VERSION 5.8 ;
BUSBITCHARS "[]" ;
DIVIDERCHAR "/" ;
UNITS
    DATABASE MICRONS 1000 ;
END UNITS

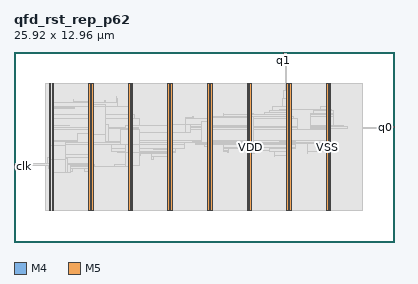
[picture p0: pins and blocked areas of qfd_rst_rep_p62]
MACRO qfd_rst_rep_p62
  FOREIGN qfd_rst_rep_p62 0 0 ;
  CLASS BLOCK ;
  SIZE 25.92 BY 12.96 ;
  PIN clk
    DIRECTION INPUT ;
    USE SIGNAL ;
    PORT
      LAYER M4 ;
        RECT  0 5.136 0.084 5.16 ;
    END
  END clk
  PIN d
    DIRECTION INPUT ;
    USE SIGNAL ;
    PORT
      LAYER M4 ;
        RECT  0 5.232 0.084 5.256 ;
    END
  END d
  PIN q0
    DIRECTION OUTPUT ;
    USE SIGNAL ;
    PORT
      LAYER M4 ;
        RECT  25.836 7.824 25.92 7.848 ;
    END
  END q0
  PIN q1
    DIRECTION OUTPUT ;
    USE SIGNAL ;
    PORT
      LAYER M5 ;
        RECT  18.384 12.876 18.408 12.96 ;
    END
  END q1
  PIN VSS
    DIRECTION INOUT ;
    USE GROUND ;
    PORT
      LAYER M5 ;
        RECT  21.3 2.137 21.42 10.823 ;
        RECT  18.6 2.137 18.72 10.823 ;
        RECT  15.9 2.137 16.02 10.823 ;
        RECT  13.2 2.137 13.32 10.823 ;
        RECT  10.5 2.137 10.62 10.823 ;
        RECT  7.8 2.137 7.92 10.823 ;
        RECT  5.1 2.137 5.22 10.823 ;
        RECT  2.4 2.137 2.52 10.823 ;
    END
  END VSS
  PIN VDD
    DIRECTION INOUT ;
    USE POWER ;
    PORT
      LAYER M5 ;
        RECT  21.492 2.151 21.612 10.809 ;
        RECT  18.792 2.151 18.912 10.809 ;
        RECT  16.092 2.151 16.212 10.809 ;
        RECT  13.392 2.151 13.512 10.809 ;
        RECT  10.692 2.151 10.812 10.809 ;
        RECT  7.992 2.151 8.112 10.809 ;
        RECT  5.292 2.151 5.412 10.809 ;
        RECT  2.592 2.151 2.712 10.809 ;
    END
  END VDD
  OBS
    LAYER RVTN ;
     RECT  2.16 2.16 23.76 2.295 ;
     RECT  2.16 2.565 23.76 2.835 ;
     RECT  2.16 3.105 23.76 3.375 ;
     RECT  2.16 3.645 23.76 3.915 ;
     RECT  2.16 4.185 23.76 4.455 ;
     RECT  2.16 4.725 23.76 4.995 ;
     RECT  2.16 5.265 23.76 5.535 ;
     RECT  2.16 5.805 23.76 6.075 ;
     RECT  2.16 6.345 23.76 6.615 ;
     RECT  2.16 6.885 23.76 7.155 ;
     RECT  2.16 7.425 23.76 7.695 ;
     RECT  2.16 7.965 23.76 8.235 ;
     RECT  2.16 8.505 23.76 8.775 ;
     RECT  2.16 9.045 23.76 9.315 ;
     RECT  2.16 9.585 23.76 9.855 ;
     RECT  2.16 10.125 23.76 10.395 ;
     RECT  2.16 10.665 23.76 10.8 ;
    LAYER RVTP ;
     RECT  2.16 2.295 23.76 2.565 ;
     RECT  2.16 2.835 23.76 3.105 ;
     RECT  2.16 3.375 23.76 3.645 ;
     RECT  2.16 3.915 23.76 4.185 ;
     RECT  2.16 4.455 23.76 4.725 ;
     RECT  2.16 4.995 23.76 5.265 ;
     RECT  2.16 5.535 23.76 5.805 ;
     RECT  2.16 6.075 23.76 6.345 ;
     RECT  2.16 6.615 23.76 6.885 ;
     RECT  2.16 7.155 23.76 7.425 ;
     RECT  2.16 7.695 23.76 7.965 ;
     RECT  2.16 8.235 23.76 8.505 ;
     RECT  2.16 8.775 23.76 9.045 ;
     RECT  2.16 9.315 23.76 9.585 ;
     RECT  2.16 9.855 23.76 10.125 ;
     RECT  2.16 10.395 23.76 10.665 ;
    LAYER M1 ;
     RECT  2.16 2.151 23.76 10.809 ;
    LAYER M2 ;
     RECT  2.16 2.151 23.76 10.809 ;
     RECT  23.76 7.776 25.835 7.794 ;
    LAYER M3 ;
     RECT  2.415 2.143 2.505 2.413 ;
     RECT  5.115 2.143 5.205 2.413 ;
     RECT  7.815 2.143 7.905 2.413 ;
     RECT  10.515 2.143 10.605 2.413 ;
     RECT  13.215 2.143 13.305 2.413 ;
     RECT  15.915 2.143 16.005 2.413 ;
     RECT  18.615 2.143 18.705 2.413 ;
     RECT  21.315 2.143 21.405 2.413 ;
     RECT  2.415 2.413 2.697 4.747 ;
     RECT  2.415 4.747 2.826 4.801 ;
     RECT  3.6 4.747 3.834 4.801 ;
     RECT  5.115 2.413 5.397 4.801 ;
     RECT  2.415 4.801 3.978 5.035 ;
     RECT  4.788 4.801 5.397 5.035 ;
     RECT  2.376 5.035 5.397 5.131 ;
     RECT  0.324 5.131 0.342 5.261 ;
     RECT  2.376 5.131 5.49 5.261 ;
     RECT  6.84 5.131 6.858 5.261 ;
     RECT  2.376 5.261 5.397 5.323 ;
     RECT  2.304 5.323 5.397 5.765 ;
     RECT  10.515 2.413 10.797 5.809 ;
     RECT  7.815 2.413 8.097 5.845 ;
     RECT  9.36 5.611 9.486 5.845 ;
     RECT  10.332 5.809 10.797 5.845 ;
     RECT  7.815 5.845 8.442 5.881 ;
     RECT  17.748 5.845 17.766 5.881 ;
     RECT  18.615 2.413 18.897 5.881 ;
     RECT  2.415 5.765 5.397 5.999 ;
     RECT  7.668 5.881 8.622 6.043 ;
     RECT  9.36 5.845 10.797 6.043 ;
     RECT  15.915 2.413 16.197 6.043 ;
     RECT  7.668 6.043 10.797 6.115 ;
     RECT  7.092 6.115 10.998 6.151 ;
     RECT  14.58 6.079 14.598 6.151 ;
     RECT  17.748 5.881 18.897 6.151 ;
     RECT  20.016 6.007 20.034 6.151 ;
     RECT  21.315 2.413 21.597 6.151 ;
     RECT  14.256 6.151 14.598 6.241 ;
     RECT  15.915 6.043 16.434 6.241 ;
     RECT  6.624 6.151 10.998 6.385 ;
     RECT  14.256 6.241 14.634 6.385 ;
     RECT  15.408 6.241 16.434 6.385 ;
     RECT  17.424 6.151 18.897 6.385 ;
     RECT  14.256 6.385 16.434 6.421 ;
     RECT  17.424 6.385 19.17 6.421 ;
     RECT  13.215 2.413 13.497 6.547 ;
     RECT  3.42 5.999 5.397 6.655 ;
     RECT  6.624 6.385 11.61 6.655 ;
     RECT  12.996 6.547 13.497 6.655 ;
     RECT  14.256 6.421 19.17 6.655 ;
     RECT  12.348 6.655 19.17 6.691 ;
     RECT  20.016 6.151 21.597 6.691 ;
     RECT  3.42 6.655 11.61 6.781 ;
     RECT  12.348 6.691 21.597 6.781 ;
     RECT  2.415 5.999 2.697 6.925 ;
     RECT  3.42 6.781 21.597 6.925 ;
     RECT  2.415 6.925 21.597 7.655 ;
     RECT  20.196 7.655 21.597 7.771 ;
     RECT  2.415 7.655 19.35 7.799 ;
     RECT  9.432 7.799 19.35 7.805 ;
     RECT  25.812 7.771 25.83 7.853 ;
     RECT  9.432 7.805 9.558 7.889 ;
     RECT  10.515 7.805 19.35 7.889 ;
     RECT  20.196 7.771 22.734 7.889 ;
     RECT  9.432 7.889 9.45 7.925 ;
     RECT  20.196 7.889 22.482 7.925 ;
     RECT  10.515 7.889 10.89 8.045 ;
     RECT  2.415 7.799 8.586 8.429 ;
     RECT  11.7 7.889 19.35 8.429 ;
     RECT  11.7 8.429 12.222 8.465 ;
     RECT  12.204 8.465 12.222 8.537 ;
     RECT  13.215 8.429 19.062 8.537 ;
     RECT  20.196 7.925 21.798 8.537 ;
     RECT  2.415 8.429 8.19 8.699 ;
     RECT  14.256 8.537 18.954 8.699 ;
     RECT  20.232 8.537 21.798 8.699 ;
     RECT  14.256 8.699 14.274 8.735 ;
     RECT  20.232 8.699 21.762 8.735 ;
     RECT  15.915 8.699 16.326 8.771 ;
     RECT  17.1 8.699 18.897 8.807 ;
     RECT  17.46 8.807 18.897 8.969 ;
     RECT  20.448 8.735 21.762 8.969 ;
     RECT  20.448 8.969 21.654 9.005 ;
     RECT  20.448 9.005 21.597 9.053 ;
     RECT  2.415 8.699 8.097 9.239 ;
     RECT  17.604 8.969 18.897 9.239 ;
     RECT  20.916 9.053 21.597 9.275 ;
     RECT  2.415 9.239 7.074 9.509 ;
     RECT  4.032 9.509 5.397 9.617 ;
     RECT  6.192 9.509 6.21 9.653 ;
     RECT  4.032 9.617 4.05 9.689 ;
     RECT  6.984 9.509 7.074 9.779 ;
     RECT  18.288 9.239 18.897 9.779 ;
     RECT  6.984 9.779 7.002 9.923 ;
     RECT  18.396 9.779 18.897 10.355 ;
     RECT  2.415 9.509 2.697 10.547 ;
     RECT  5.115 9.617 5.397 10.547 ;
     RECT  7.815 9.239 8.097 10.547 ;
     RECT  10.515 8.045 10.797 10.547 ;
     RECT  13.215 8.537 13.497 10.547 ;
     RECT  15.915 8.771 16.197 10.547 ;
     RECT  18.54 10.355 18.897 10.547 ;
     RECT  21.315 9.275 21.597 10.547 ;
     RECT  2.415 10.547 2.505 10.817 ;
     RECT  5.115 10.547 5.205 10.817 ;
     RECT  7.815 10.547 7.905 10.817 ;
     RECT  10.515 10.547 10.605 10.817 ;
     RECT  13.215 10.547 13.305 10.817 ;
     RECT  15.915 10.547 16.005 10.817 ;
     RECT  18.54 10.547 18.705 10.817 ;
     RECT  21.315 10.547 21.405 10.817 ;
     RECT  18.54 10.817 18.558 12.845 ;
    LAYER M4 ;
     RECT  0.06 5.136 0.133 5.256 ;
     RECT  0.133 5.136 0.353 5.352 ;
     RECT  0.353 5.232 2.408 5.352 ;
     RECT  2.408 2.148 2.512 10.812 ;
     RECT  2.512 2.418 2.704 10.542 ;
     RECT  2.704 4.752 3.539 6.84 ;
     RECT  3.539 4.752 3.629 5.688 ;
     RECT  2.704 7.92 3.809 7.944 ;
     RECT  3.629 4.752 3.845 5.256 ;
     RECT  2.704 9.12 4.097 9.144 ;
     RECT  3.539 6.816 4.309 6.84 ;
     RECT  3.845 5.232 5.108 5.256 ;
     RECT  4.309 6.816 5.108 7.368 ;
     RECT  5.101 9.36 5.108 9.384 ;
     RECT  5.108 2.148 5.212 10.812 ;
     RECT  5.212 2.418 5.404 10.542 ;
     RECT  5.404 5.136 5.501 5.256 ;
     RECT  5.404 6.816 6.221 7.992 ;
     RECT  5.404 9.216 6.221 9.384 ;
     RECT  6.221 9.216 6.227 9.24 ;
     RECT  6.221 6.864 6.437 7.992 ;
     RECT  5.501 5.136 6.829 5.16 ;
     RECT  6.437 6.864 7.244 7.752 ;
     RECT  7.244 6.672 7.585 7.752 ;
     RECT  6.829 5.136 7.621 5.256 ;
     RECT  7.585 6.672 7.621 7.944 ;
     RECT  7.621 5.136 7.808 7.944 ;
     RECT  7.808 2.148 7.912 10.812 ;
     RECT  7.912 2.418 8.104 10.542 ;
     RECT  8.104 5.232 8.579 6.168 ;
     RECT  8.579 6.144 9.209 6.168 ;
     RECT  9.529 6.288 10.508 6.312 ;
     RECT  8.104 7.44 10.508 7.944 ;
     RECT  10.508 2.148 10.612 10.812 ;
     RECT  10.612 2.418 10.804 10.542 ;
     RECT  10.804 7.44 11.729 8.04 ;
     RECT  11.729 7.44 12.053 7.992 ;
     RECT  12.193 6.816 12.337 6.84 ;
     RECT  12.053 7.872 12.757 7.992 ;
     RECT  12.337 6.768 13.208 6.84 ;
     RECT  12.757 7.872 13.208 8.184 ;
     RECT  13.208 2.148 13.312 10.812 ;
     RECT  13.312 2.418 13.504 10.542 ;
     RECT  13.504 6.816 15.908 6.84 ;
     RECT  13.504 7.968 15.908 8.52 ;
     RECT  15.908 2.148 16.012 10.812 ;
     RECT  16.012 2.418 16.204 10.542 ;
     RECT  16.204 6.24 16.355 6.84 ;
     RECT  16.204 7.968 16.355 8.568 ;
     RECT  16.355 6.24 17.453 6.264 ;
     RECT  16.355 8.544 17.489 8.568 ;
     RECT  18.373 12.816 18.569 12.84 ;
     RECT  18.097 6.816 18.608 6.84 ;
     RECT  18.133 9.024 18.608 9.048 ;
     RECT  18.608 2.148 18.712 10.812 ;
     RECT  18.712 2.418 18.904 10.542 ;
     RECT  18.904 6.816 19.181 6.84 ;
     RECT  20.221 7.776 21.308 7.8 ;
     RECT  18.904 9.024 21.308 9.048 ;
     RECT  21.308 2.148 21.412 10.812 ;
     RECT  21.412 2.418 21.604 10.542 ;
     RECT  25.801 7.824 25.884 7.848 ;
    LAYER M5 ;
     RECT  2.4 2.137 2.52 2.151 ;
     RECT  5.1 2.137 5.22 2.151 ;
     RECT  7.8 2.137 7.92 2.151 ;
     RECT  10.5 2.137 10.62 2.151 ;
     RECT  13.2 2.137 13.32 2.151 ;
     RECT  15.9 2.137 16.02 2.151 ;
     RECT  18.6 2.137 18.72 2.151 ;
     RECT  21.3 2.137 21.42 2.151 ;
     RECT  7.8 2.151 8.112 5.221 ;
     RECT  0.144 5.221 0.168 5.363 ;
     RECT  2.4 2.151 2.712 5.653 ;
     RECT  7.8 5.221 8.568 6.085 ;
     RECT  15.9 2.151 16.212 6.229 ;
     RECT  2.4 5.653 3.528 6.563 ;
     RECT  7.632 6.085 8.568 6.661 ;
     RECT  13.2 2.151 13.512 6.757 ;
     RECT  5.1 2.151 5.412 7.333 ;
     RECT  7.296 6.661 8.568 7.667 ;
     RECT  7.296 7.667 8.472 7.763 ;
     RECT  7.8 7.763 8.472 7.811 ;
     RECT  12.768 6.757 13.512 8.195 ;
     RECT  15.9 6.229 16.344 8.579 ;
     RECT  5.1 7.333 6.216 9.251 ;
     RECT  2.4 6.563 2.712 10.809 ;
     RECT  5.1 9.251 5.412 10.809 ;
     RECT  7.8 7.811 8.112 10.809 ;
     RECT  10.5 2.151 10.812 10.809 ;
     RECT  13.2 8.195 13.512 10.809 ;
     RECT  15.9 8.579 16.212 10.809 ;
     RECT  18.6 2.151 18.912 10.809 ;
     RECT  21.3 2.151 21.612 10.809 ;
     RECT  2.4 10.809 2.52 10.823 ;
     RECT  5.1 10.809 5.22 10.823 ;
     RECT  7.8 10.809 7.92 10.823 ;
     RECT  10.5 10.809 10.62 10.823 ;
     RECT  13.2 10.809 13.32 10.823 ;
     RECT  15.9 10.809 16.02 10.823 ;
     RECT  18.6 10.809 18.72 10.823 ;
     RECT  21.3 10.809 21.42 10.823 ;
     RECT  18.384 12.805 18.408 12.944 ;
  END
END qfd_rst_rep_p62
END LIBRARY
